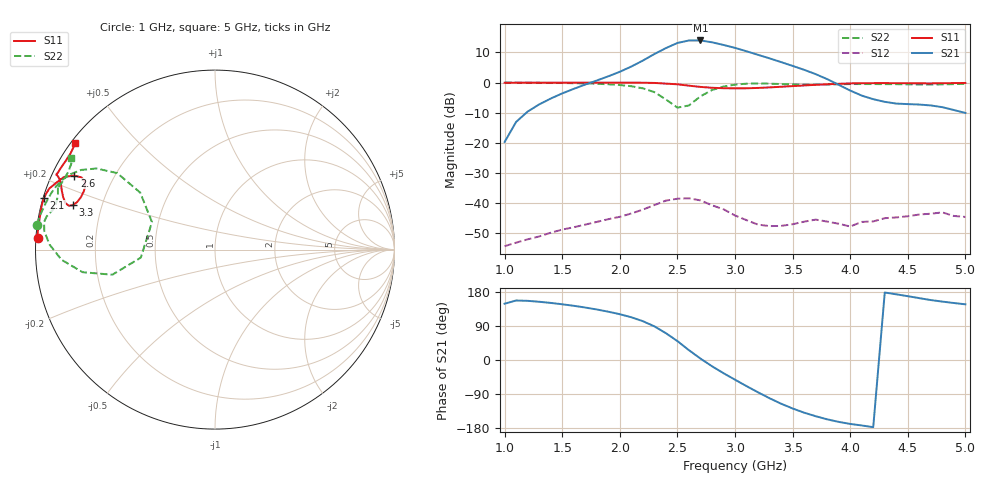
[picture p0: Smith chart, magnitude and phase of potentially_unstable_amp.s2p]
! splotRF Created Sat May 23 08:36:33 2026
# GHz S ma R 50
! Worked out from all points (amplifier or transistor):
!   41 points, 1 GHz to 5 GHz, reference 50 ohm
!   highest |S21| = 14.0 dB at 2.7 GHz (marker M1)
!   |S21| within 3 dB of that: 2.377 GHz to 3.047 GHz (670.4 MHz wide, 24.7 % of centre)
!   unconditionally stable (mu >= 1): 2.304 GHz to 3.629 GHz; 4.417 GHz to 4.944 GHz
!   at 1.6 GHz: K = 0.56, MSG = 23.0 dB, |S12| = -48.1 dB
!   at 3 GHz: K = 1.58, MAG = 23.4 dB, |S12| = -44.2 dB
!   at 5 GHz: K = 0.77, MSG = 17.3 dB, |S12| = -44.6 dB
!   S11 on the Smith chart (normalised r, x): 1 GHz: 0.00, +0.03; 2.1 GHz: 0.00, +0.15; 2.6 GHz: 0.06, +0.25; 3.3 GHz: 0.10, +0.15; 5 GHz: 0.01, +0.34
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1  0.9907 176.4  0.1029 148.5  0.001914 81.9  0.9986 172.0
1.2  0.9923 174.0  0.3286 156.1  0.002485 76.4  0.9946 169.4
1.7  0.9946 166.8  0.9247 138.4  0.004367 67.6  0.9649 160.9
1.9  0.9964 165.0  1.268 127.5  0.00537 61.8  0.9344 155.3
2.1  0.9952 163.2  1.841 112.8  0.006682 52.8  0.8674 149.2
2.2  0.9912 161.7  2.312 102.5  0.00774 45.1  0.8004 145.6
2.3  0.9839 159.7  2.968 88.9  0.009215 35.2  0.6918 142.0
2.4  0.9593 157.1  3.725 70.8  0.01092 15.4  0.5234 142.7
2.5  0.9337 154.3  4.537 49.9  0.01174 4.3  0.3829 156.5
2.6  0.8862 152.2  4.989 26.0  0.01195 -18.5  0.4159 -173.8
2.7  0.8451 151.6  4.993 3.8  0.01102 -37.0  0.5892 -166.2
2.8  0.8179 152.4  4.655 -16.4  0.009144 -57.5  0.7484 -170.3
2.9  0.8037 154.2  4.203 -34.7  0.007846 -76.8  0.8571 -176.2
3  0.7999 156.1  3.76 -52.0  0.006191 -97.2  0.922 178.3
3.1  0.8019 158.6  3.3 -68.9  0.005172 -121.8  0.9564 173.9
3.2  0.8126 161.0  2.882 -85.3  0.004361 -147.3  0.9646 170.8
3.3  0.8294 162.6  2.518 -100.9  0.004122 -177.1  0.9561 168.9
3.5  0.8717 162.8  1.886 -127.9  0.004428 137.7  0.9311 166.3
3.7  0.9148 158.9  1.378 -148.3  0.005285 103.5  0.9229 162.8
4  0.9659 155.0  0.7356 -168.7  0.004058 86.4  0.9421 158.3
4.4  0.9742 153.8  0.4467 173.4  0.005747 62.4  0.9384 158.0
5  0.9833 142.7  0.3122 147.0  0.005857 59.4  0.9505 147.3
